VERSION 5.7 ;
  NOWIREEXTENSIONATPIN ON ;
  DIVIDERCHAR "/" ;
  BUSBITCHARS "[]" ;
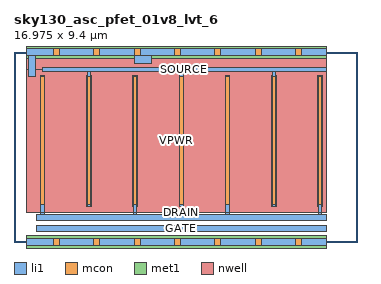
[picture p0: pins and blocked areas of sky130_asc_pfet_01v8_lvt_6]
MACRO sky130_asc_pfet_01v8_lvt_6
  CLASS CORE ;
  FOREIGN sky130_asc_pfet_01v8_lvt_6 ;
  ORIGIN 0.000 0.000 ;
  SIZE 16.975 BY 9.400 ;
  SITE unitasc ;
  PIN GATE
    DIRECTION INOUT ;
    USE SIGNAL ;
    ANTENNAGATEAREA 77.400002 ;
    PORT
      LAYER li1 ;
        RECT 1.090 0.520 15.470 0.820 ;
    END
  END GATE
  PIN SOURCE
    DIRECTION INOUT ;
    USE SIGNAL ;
    ANTENNADIFFAREA 5.611500 ;
    PORT
      LAYER li1 ;
        RECT 1.390 8.450 15.470 8.650 ;
        RECT 3.615 1.755 3.785 8.450 ;
        RECT 8.195 1.755 8.365 8.450 ;
        RECT 12.775 1.755 12.945 8.450 ;
      LAYER mcon ;
        RECT 3.615 1.835 3.785 8.165 ;
        RECT 8.195 1.835 8.365 8.165 ;
        RECT 12.775 1.835 12.945 8.165 ;
      LAYER met1 ;
        RECT 3.585 1.775 3.815 8.225 ;
        RECT 8.165 1.775 8.395 8.225 ;
        RECT 12.745 1.775 12.975 8.225 ;
    END
  END SOURCE
  PIN DRAIN
    DIRECTION INOUT ;
    USE SIGNAL ;
    ANTENNADIFFAREA 7.482000 ;
    PORT
      LAYER li1 ;
        RECT 1.325 1.350 1.495 8.245 ;
        RECT 5.905 1.350 6.075 8.245 ;
        RECT 10.485 1.350 10.655 8.245 ;
        RECT 15.065 1.350 15.235 8.245 ;
        RECT 1.090 1.050 15.470 1.350 ;
      LAYER mcon ;
        RECT 1.325 1.835 1.495 8.165 ;
        RECT 5.905 1.835 6.075 8.165 ;
        RECT 10.485 1.835 10.655 8.165 ;
        RECT 15.065 1.835 15.235 8.165 ;
      LAYER met1 ;
        RECT 1.295 1.775 1.525 8.225 ;
        RECT 5.875 1.775 6.105 8.225 ;
        RECT 10.455 1.775 10.685 8.225 ;
        RECT 15.035 1.775 15.265 8.225 ;
    END
  END DRAIN
  PIN VPWR
    DIRECTION INOUT ;
    USE POWER ;
    PORT
      LAYER nwell ;
        RECT 0.600 8.535 15.470 9.700 ;
        RECT 0.600 1.470 15.475 8.535 ;
        RECT 1.085 1.465 15.475 1.470 ;
      LAYER li1 ;
        RECT 0.600 9.250 15.470 9.550 ;
        RECT 0.740 8.200 1.040 9.250 ;
        RECT 5.980 8.850 6.780 9.250 ;
      LAYER mcon ;
        RECT 1.940 9.250 2.240 9.550 ;
        RECT 3.940 9.250 4.240 9.550 ;
        RECT 5.940 9.250 6.240 9.550 ;
        RECT 7.940 9.250 8.240 9.550 ;
        RECT 9.940 9.250 10.240 9.550 ;
        RECT 11.940 9.250 12.240 9.550 ;
        RECT 13.940 9.250 14.240 9.550 ;
      LAYER met1 ;
        RECT 0.600 9.100 15.470 9.700 ;
    END
  END VPWR
  PIN VGND
    DIRECTION INOUT ;
    USE GROUND ;
    PORT
      LAYER li1 ;
        RECT 0.600 -0.150 15.470 0.150 ;
      LAYER mcon ;
        RECT 1.940 -0.150 2.240 0.150 ;
        RECT 3.940 -0.150 4.240 0.150 ;
        RECT 5.940 -0.150 6.240 0.150 ;
        RECT 7.940 -0.150 8.240 0.150 ;
        RECT 9.940 -0.150 10.240 0.150 ;
        RECT 11.940 -0.150 12.240 0.150 ;
        RECT 13.940 -0.150 14.240 0.150 ;
      LAYER met1 ;
        RECT 0.600 -0.300 15.470 0.300 ;
    END
  END VGND
END sky130_asc_pfet_01v8_lvt_6
END LIBRARY

